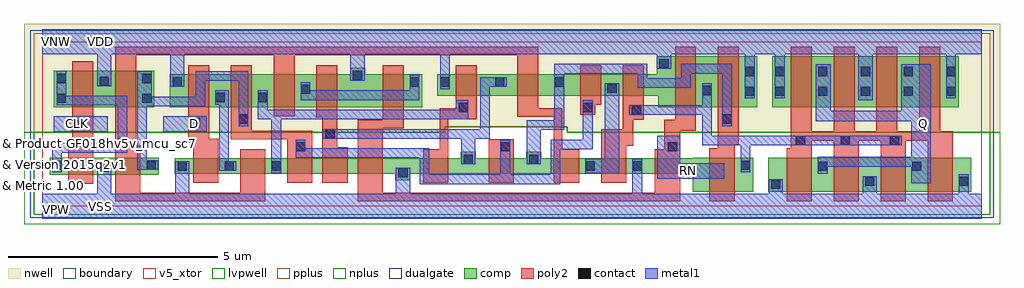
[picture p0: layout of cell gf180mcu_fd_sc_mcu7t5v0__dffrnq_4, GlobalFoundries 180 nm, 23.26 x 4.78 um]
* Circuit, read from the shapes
.subckt gf180mcu_fd_sc_mcu7t5v0__dffrnq_4 CLK D Q RN VDD VNW VSS
XM1 VSS CLK n1 VSUBS nfet_05v0 w=0.405u l=0.6u
XM2 n2 n1 VSS VSUBS nfet_05v0 w=0.405u l=0.6u
XM3 n3 D VSS VSUBS nfet_05v0 w=0.36u l=0.6u
XM4 n4 n1 n3 VSUBS nfet_05v0 w=0.36u l=0.6u
XM5 n5 n2 n4 VSUBS nfet_05v0 w=0.36u l=0.6u
XM6 n6 n7 n5 VSUBS nfet_05v0 w=0.36u l=0.6u
XM7 VSS RN n6 VSUBS nfet_05v0 w=0.36u l=0.6u
XM8 n7 n4 VSS VSUBS nfet_05v0 w=0.36u l=0.6u
XM9 n8 n2 n7 VSUBS nfet_05v0 w=0.36u l=0.6u
XM10 n9 n1 n8 VSUBS nfet_05v0 w=0.36u l=0.6u
XM11 VSS n10 n9 VSUBS nfet_05v0 w=0.36u l=0.6u
XM12 n11 RN VSS VSUBS nfet_05v0 w=0.36u l=0.6u
XM13 n10 n8 n11 VSUBS nfet_05v0 w=0.815u l=0.6u
XM14 Q n10 VSS VSUBS nfet_05v0 w=0.815u l=0.6u m=4
XM15 VDD CLK n1 VNW pfet_05v0 w=0.865u l=0.5u
XM16 n2 n1 VDD VNW pfet_05v0 w=0.865u l=0.5u
XM17 n3 D VDD VNW pfet_05v0 w=0.78u l=0.5u
XM18 n4 n2 n3 VNW pfet_05v0 w=0.78u l=0.5u
XM19 n12 n1 n4 VNW pfet_05v0 w=0.78u l=0.5u
XM20 VDD n7 n12 VNW pfet_05v0 w=0.78u l=0.5u
XM21 n12 RN VDD VNW pfet_05v0 w=0.78u l=0.5u
XM22 n7 n4 VDD VNW pfet_05v0 w=0.505u l=0.5u
XM23 n8 n1 n7 VNW pfet_05v0 w=0.505u l=0.5u
XM24 n9 n2 n8 VNW pfet_05v0 w=0.505u l=0.5u
XM25 VDD n10 n9 VNW pfet_05v0 w=0.505u l=0.5u
XM26 n10 RN VDD VNW pfet_05v0 w=1.215u l=0.5u
XM27 VDD n8 n10 VNW pfet_05v0 w=1.215u l=0.5u
XM28 Q n10 VDD VNW pfet_05v0 w=1.215u l=0.5u m=4
.ends

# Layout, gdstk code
import gdstk
lib = gdstk.Library(unit=1e-6, precision=5e-09)
def R(c, l, rs):  # rectangles x0, y0, x1, y1
    for r in rs: c.add(gdstk.rectangle(r[:2], r[2:], *l))
def A(c, l, x, y, w, h, nx, ny, dx, dy):  # array of equal rectangles
    R(c, l, [(x+i*dx, y+j*dy, x+i*dx+w, y+j*dy+h) for i in range(nx) for j in range(ny)])
def P(c, l, *ps):  # polygons
    for p in ps: c.add(gdstk.Polygon(p, *l))
boundary = (0, 0)
nwell = (21, 0)
comp = (22, 0)
poly2 = (30, 0)
pplus = (31, 0)
nplus = (32, 0)
contact = (33, 0)
metal1 = (34, 0)
dualgate = (55, 0)
v5_xtor = (112, 1)
lvpwell = (204, 0)

gf180mcu_fd_sc_mcu7t5v0_ = lib.new_cell('gf180mcu_fd_sc_mcu7t5v0__dffrnq_4')
R(gf180mcu_fd_sc_mcu7t5v0_, boundary, [(0,0,22.4,3.92)])
P(gf180mcu_fd_sc_mcu7t5v0_, nwell, [(-0.43,1.76),(-0.43,4.35),(22.83,4.35),(22.83,1.76),(12.515,1.76),(12.515,1.895),(9.6,1.895),(9.6,1.76)])
R(gf180mcu_fd_sc_mcu7t5v0_, comp, [(17.305,0.345,22.145,1.16), (0.18,0.755,2.78,1.16), (0.28,2.36,2.68,3.225), (17.405,2.36,21.845,3.575)])
P(gf180mcu_fd_sc_mcu7t5v0_, comp, [(3.04,2.36),(3.04,3.14),(7.34,3.14),(7.34,3.3),(7.7,3.3),(7.7,3.14),(9.06,3.14),(9.06,2.36)],
  [(15.505,0.345),(15.505,0.78),(8.78,0.78),(8.78,0.62),(8.42,0.62),(8.42,0.78),(3.16,0.78),(3.16,1.14),(9.98,1.14),(9.98,1.295),(10.34,1.295),(10.34,1.14),(11.54,1.14),(11.54,1.295),(11.9,1.295),(11.9,1.14),(15.505,1.14),(15.505,1.16),(16.945,1.16),(16.945,0.345)],
  [(14.685,2.36),(14.685,2.635),(9.42,2.635),(9.42,3.14),(14.645,3.14),(14.645,3.575),(17.045,3.575),(17.045,2.36)])
R(gf180mcu_fd_sc_mcu7t5v0_, poly2, [(10.64,0.56,11.24,1.6)])
P(gf180mcu_fd_sc_mcu7t5v0_, poly2, [(0.62,0.535),(0.62,1.44),(0.72,1.44),(0.72,3.45),(1.22,3.45),(1.22,0.535)],
  [(3.6,0.56),(3.6,1.51),(3.48,1.51),(3.48,3.36),(3.98,3.36),(3.98,1.61),(4.2,1.61),(4.2,0.56)],
  [(5.84,0.56),(5.84,1.6),(4.5,1.6),(4.5,3.36),(5,3.36),(5,1.8),(6.44,1.8),(6.44,0.56)],
  [(6.68,0.56),(6.68,2.115),(6.54,2.115),(6.54,3.36),(7.04,3.36),(7.04,1.4),(7.28,1.4),(7.28,0.56)],
  [(9.08,0.56),(9.08,1.36),(9.48,1.36),(9.48,2.335),(9.86,2.335),(9.86,3.36),(10.36,3.36),(10.36,2.07),(9.68,2.07),(9.68,0.56)],
  [(1.74,0.12),(1.74,3.8),(11.82,3.8),(11.82,2.335),(12.4,2.335),(12.4,1.36),(12.8,1.36),(12.8,0.56),(12.2,0.56),(12.2,2.135),(11.32,2.135),(11.32,3.6),(6.02,3.6),(6.02,2.14),(5.52,2.14),(5.52,3.6),(2.24,3.6),(2.24,1.44),(2.34,1.44),(2.34,0.32),(4.72,0.32),(4.72,1.36),(5.32,1.36),(5.32,0.12)],
  [(12.825,2.175),(12.825,3.36),(13.325,3.36),(13.325,2.415),(13.185,2.415),(13.185,2.175)],
  [(13.325,0.56),(13.325,1.84),(13.845,1.84),(13.845,3.36),(14.345,3.36),(14.345,2.06),(14.085,2.06),(14.085,1.44),(13.925,1.44),(13.925,0.56)],
  [(7.52,0.12),(7.52,2.06),(8.12,2.06),(8.12,3.36),(8.62,3.36),(8.62,1.86),(8.12,1.86),(8.12,0.32),(14.605,0.32),(14.605,1.36),(14.825,1.36),(14.825,2.06),(15.085,2.06),(15.085,3.8),(15.585,3.8),(15.585,1.805),(15.205,1.805),(15.205,0.12)],
  [(15.905,0.12),(15.905,1.38),(16.105,1.38),(16.105,3.8),(16.605,3.8),(16.605,1.46),(16.505,1.46),(16.505,0.12)],
  [(17.745,0.12),(17.745,1.38),(17.845,1.38),(17.845,3.8),(18.345,3.8),(18.345,1.785),(18.865,1.785),(18.865,3.8),(19.365,3.8),(19.365,1.785),(19.885,1.785),(19.885,3.8),(20.385,3.8),(20.385,1.79),(20.905,1.79),(20.905,3.8),(21.405,3.8),(21.405,1.785),(21.705,1.785),(21.705,0.12),(21.105,0.12),(21.105,1.555),(20.585,1.555),(20.585,0.12),(19.985,0.12),(19.985,1.555),(19.465,1.555),(19.465,0.12),(18.865,0.12),(18.865,1.555),(18.345,1.555),(18.345,0.12)])
P(gf180mcu_fd_sc_mcu7t5v0_, pplus, [(-0.2,1.76),(-0.2,4.12),(22.6,4.12),(22.6,1.76),(12.515,1.76),(12.515,1.895),(9.6,1.895),(9.6,1.76)])
P(gf180mcu_fd_sc_mcu7t5v0_, nplus, [(-0.2,-0.2),(-0.2,1.76),(9.6,1.76),(9.6,1.895),(12.515,1.895),(12.515,1.76),(22.6,1.76),(22.6,-0.2)])
A(gf180mcu_fd_sc_mcu7t5v0_, contact, 3.23, 0.85, 0.22, 0.22, 3, 1, 1.12, 0)
A(gf180mcu_fd_sc_mcu7t5v0_, contact, 17.475, 2.63, 0.22, 0.22, 5, 2, 1.02, 0.47)
R(gf180mcu_fd_sc_mcu7t5v0_, contact, [(17.375,0.415,17.595,0.635), (19.615,0.485,19.835,0.705), (21.855,0.485,22.075,0.705), (8.49,0.69,8.71,0.91), (1.37,0.825,1.59,1.045), (18.495,0.84,18.715,1.06), (20.735,0.84,20.955,1.06), (12.955,0.85,13.175,1.07), (14.075,0.85,14.295,1.07), (0.25,0.87,0.47,1.09), (2.49,0.87,2.71,1.09), (16.655,0.87,16.875,1.09), (10.05,1.005,10.27,1.225), (11.61,1.005,11.83,1.225), (6.05,1.31,6.27,1.53), (10.93,1.31,11.15,1.53), (14.915,1.31,15.135,1.53), (1.81,1.405,2.03,1.625), (17.965,1.455,18.185,1.675), (19.03,1.455,19.25,1.675), (20.205,1.455,20.425,1.675), (6.75,1.615,6.97,1.835), (0.79,1.835,1.01,2.055), (3.55,1.885,3.77,2.105), (4.69,1.97,4.91,2.19), (16.215,1.97,16.435,2.19), (14.055,2.18,14.275,2.4), (9.93,2.245,10.15,2.465), (12.895,2.245,13.115,2.465), (0.35,2.465,0.57,2.685), (2.39,2.465,2.61,2.685), (4.13,2.48,4.35,2.7), (5.15,2.48,5.37,2.7), (16.755,2.63,16.975,2.85), (15.735,2.65,15.955,2.87), (6.17,2.675,6.39,2.895), (13.475,2.705,13.695,2.925), (3.11,2.85,3.33,3.07), (8.77,2.85,8.99,3.07), (9.49,2.85,9.71,3.07), (10.8,2.85,11.02,3.07), (12.215,2.85,12.435,3.07), (1.37,2.87,1.59,3.09), (0.35,2.935,0.57,3.155), (2.39,2.935,2.61,3.155), (7.41,3.01,7.63,3.23), (16.755,3.1,16.975,3.32), (14.715,3.285,14.935,3.505)])
R(gf180mcu_fd_sc_mcu7t5v0_, metal1, [(0.28,1.77,1.57,2.15), (2.89,1.77,3.92,2.15)])
P(gf180mcu_fd_sc_mcu7t5v0_, metal1, [(0.245,0.81),(0.245,1.51),(1.805,1.51),(1.805,2.405),(0.345,2.405),(0.345,3.225),(0.575,3.225),(0.575,2.635),(2.035,2.635),(2.035,1.28),(0.475,1.28),(0.475,0.81)],
  [(4.225,0.845),(4.225,2.42),(4.125,2.42),(4.125,2.76),(4.455,2.76),(4.455,1.075),(4.63,1.075),(4.63,0.845)],
  [(2.265,0.865),(2.265,3.215),(2.615,3.215),(2.615,2.615),(3.665,2.615),(3.665,3.22),(4.915,3.22),(4.915,1.91),(4.685,1.91),(4.685,2.99),(3.895,2.99),(3.895,2.385),(2.495,2.385),(2.495,1.095),(2.77,1.095),(2.77,0.865)],
  [(6.165,2.53),(6.165,2.955),(6.395,2.955),(6.395,2.76),(8.765,2.76),(8.765,3.13),(8.995,3.13),(8.995,2.53)],
  [(5.465,0.79),(5.465,2.07),(5.145,2.07),(5.145,2.76),(5.375,2.76),(5.375,2.3),(9.855,2.3),(9.855,2.525),(10.155,2.525),(10.155,2.07),(5.695,2.07),(5.695,0.79)],
  [(9.99,1),(9.99,1.61),(6.69,1.61),(6.69,1.84),(10.44,1.84),(10.44,3.075),(11.08,3.075),(11.08,2.845),(10.67,2.845),(10.67,1.61),(10.33,1.61),(10.33,1)],
  [(9,0.53),(9,1.15),(6.045,1.15),(6.045,1.59),(6.275,1.59),(6.275,1.38),(9.23,1.38),(9.23,0.76),(10.925,0.76),(10.925,1.59),(11.155,1.59),(11.155,0.76),(12.12,0.76),(12.12,1.59),(12.89,1.59),(12.89,2.525),(13.12,2.525),(13.12,1.36),(12.35,1.36),(12.35,0.53)],
  [(12.95,0.79),(12.95,1.13),(13.415,1.13),(13.415,2.93),(13.755,2.93),(13.755,0.79)],
  [(14.66,0.66),(14.66,1.685),(15.21,1.685),(15.21,1.025),(16.255,1.025),(16.255,0.66)],
  [(11.55,1),(11.55,2.05),(12.21,2.05),(12.21,3.39),(14.425,3.39),(14.425,3.05),(15.235,3.05),(15.235,3.39),(16.44,3.39),(16.44,1.91),(16.21,1.91),(16.21,3.16),(15.465,3.16),(15.465,2.82),(14.195,2.82),(14.195,3.16),(12.44,3.16),(12.44,1.82),(11.89,1.82),(11.89,1)],
  [(16.65,0.81),(16.65,1.45),(15.73,1.45),(15.73,2.175),(13.995,2.175),(13.995,2.405),(15.73,2.405),(15.73,2.93),(15.96,2.93),(15.96,1.68),(20.485,1.68),(20.485,1.45),(16.88,1.45),(16.88,0.81)],
  [(20.715,0.55),(20.715,0.94),(18.72,0.94),(18.72,0.78),(18.49,0.78),(18.49,1.175),(20.715,1.175),(20.715,2.03),(18.435,2.03),(18.435,3.38),(18.8,3.38),(18.8,2.28),(20.475,2.28),(20.475,3.38),(21.18,3.38),(21.18,0.55)],
  [(0,-0.3),(0,0.3),(1.31,0.3),(1.31,1.05),(1.655,1.05),(1.655,0.3),(3.17,0.3),(3.17,1.075),(3.51,1.075),(3.51,0.3),(8.43,0.3),(8.43,0.915),(8.77,0.915),(8.77,0.3),(14.07,0.3),(14.07,1.13),(14.3,1.13),(14.3,0.3),(17.315,0.3),(17.315,0.64),(17.655,0.64),(17.655,0.3),(19.555,0.3),(19.555,0.71),(19.895,0.71),(19.895,0.3),(21.85,0.3),(21.85,0.765),(22.08,0.765),(22.08,0.3),(22.4,0.3),(22.4,-0.3)],
  [(19.455,2.53),(19.455,3.62),(17.7,3.62),(17.7,2.57),(17.465,2.57),(17.465,3.62),(16.985,3.62),(16.985,2.57),(16.75,2.57),(16.75,3.62),(14.995,3.62),(14.995,3.28),(14.655,3.28),(14.655,3.62),(9.715,3.62),(9.715,2.79),(9.485,2.79),(9.485,3.62),(7.69,3.62),(7.69,2.99),(7.35,2.99),(7.35,3.62),(3.39,3.62),(3.39,2.845),(3.05,2.845),(3.05,3.62),(1.65,3.62),(1.65,2.865),(1.31,2.865),(1.31,3.62),(0,3.62),(0,4.22),(22.4,4.22),(22.4,3.62),(21.78,3.62),(21.78,2.57),(21.55,2.57),(21.55,3.62),(19.795,3.62),(19.795,2.53)])
R(gf180mcu_fd_sc_mcu7t5v0_, dualgate, [(-0.28,-0.28,22.68,4.2)])
R(gf180mcu_fd_sc_mcu7t5v0_, v5_xtor, [(0,0,22.4,3.92)])
P(gf180mcu_fd_sc_mcu7t5v0_, lvpwell, [(-0.43,-0.43),(-0.43,1.76),(9.6,1.76),(9.6,1.895),(12.515,1.895),(12.515,1.76),(22.83,1.76),(22.83,-0.43)])
gf180mcu_fd_sc_mcu7t5v0_.add(gdstk.Label('D', (3.64,1.96), layer=34, texttype=10))
gf180mcu_fd_sc_mcu7t5v0_.add(gdstk.Label('Q', (21,1.96), layer=34, texttype=10))
gf180mcu_fd_sc_mcu7t5v0_.add(gdstk.Label('RN', (15.4,0.84), layer=34, texttype=10))
gf180mcu_fd_sc_mcu7t5v0_.add(gdstk.Label('VDD', (1.4,3.92), layer=34, texttype=10))
gf180mcu_fd_sc_mcu7t5v0_.add(gdstk.Label('VSS', (1.4,0), layer=34, texttype=10))
gf180mcu_fd_sc_mcu7t5v0_.add(gdstk.Label('CLK', (0.84,1.96), layer=34, texttype=10))
gf180mcu_fd_sc_mcu7t5v0_.add(gdstk.Label('& Vendor GLOBALFOUNDRIES', (0,2), layer=63, texttype=63))
gf180mcu_fd_sc_mcu7t5v0_.add(gdstk.Label('& Product GF018hv5v_mcu_sc7', (0,1.5), layer=63, texttype=63))
gf180mcu_fd_sc_mcu7t5v0_.add(gdstk.Label('& Version 2015q2v1', (0,1), layer=63, texttype=63))
gf180mcu_fd_sc_mcu7t5v0_.add(gdstk.Label('& Metric 1.00', (0,0.5), layer=63, texttype=63))
gf180mcu_fd_sc_mcu7t5v0_.add(gdstk.Label('VNW', (0.345,3.92), layer=21, texttype=10))
gf180mcu_fd_sc_mcu7t5v0_.add(gdstk.Label('VPW', (0.34,-0.085), layer=204, texttype=10))

lib.write_gds('gf180mcu_fd_sc_mcu7t5v0__dffrnq_4.gds')
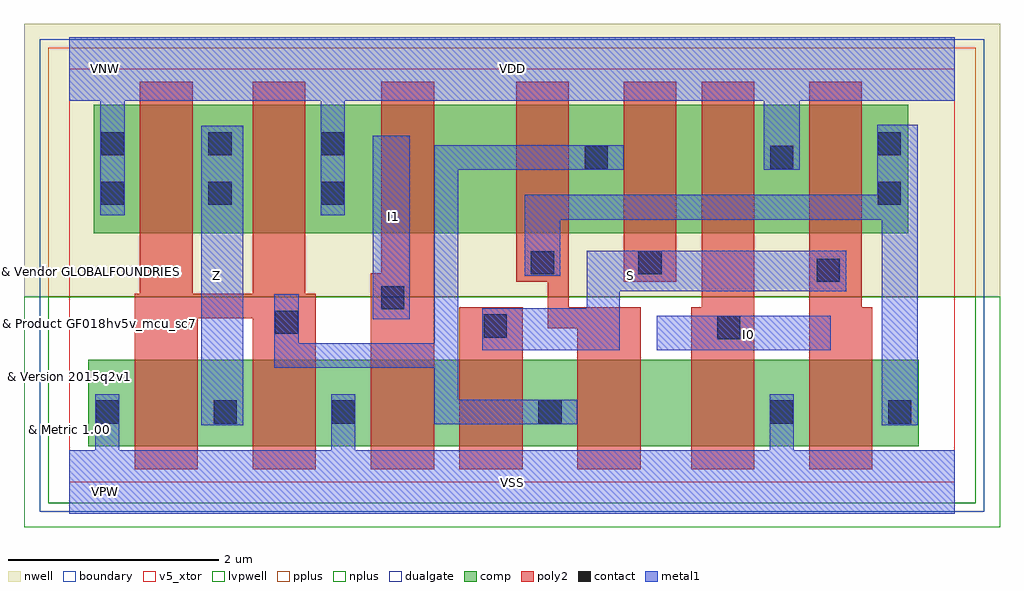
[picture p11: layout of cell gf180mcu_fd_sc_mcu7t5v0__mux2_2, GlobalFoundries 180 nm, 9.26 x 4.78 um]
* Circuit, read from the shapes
.subckt gf180mcu_fd_sc_mcu7t5v0__mux2_2 I0 I1 S VDD VNW VSS Z
XM1 Z n1 VSS VSUBS nfet_05v0 w=0.82u l=0.6u m=2
XM2 n2 I1 VSS VSUBS nfet_05v0 w=0.82u l=0.6u
XM3 n1 S n2 VSUBS nfet_05v0 w=0.82u l=0.6u
XM4 n3 n4 n1 VSUBS nfet_05v0 w=0.82u l=0.6u
XM5 VSS I0 n3 VSUBS nfet_05v0 w=0.82u l=0.6u
XM6 n4 S VSS VSUBS nfet_05v0 w=0.82u l=0.6u
XM7 Z n1 VDD VNW pfet_05v0 w=1.22u l=0.5u m=2
XM8 n5 I1 VDD VNW pfet_05v0 w=1.22u l=0.5u
XM9 n1 n4 n5 VNW pfet_05v0 w=1.22u l=0.5u
XM10 n6 S n1 VNW pfet_05v0 w=1.22u l=0.5u
XM11 VDD I0 n6 VNW pfet_05v0 w=1.22u l=0.5u
XM12 n4 S VDD VNW pfet_05v0 w=1.22u l=0.5u
.ends

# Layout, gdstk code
import gdstk
lib = gdstk.Library(unit=1e-6, precision=5e-09)
def R(c, l, rs):  # rectangles x0, y0, x1, y1
    for r in rs: c.add(gdstk.rectangle(r[:2], r[2:], *l))
def A(c, l, x, y, w, h, nx, ny, dx, dy):  # array of equal rectangles
    R(c, l, [(x+i*dx, y+j*dy, x+i*dx+w, y+j*dy+h) for i in range(nx) for j in range(ny)])
def P(c, l, *ps):  # polygons
    for p in ps: c.add(gdstk.Polygon(p, *l))
boundary = (0, 0)
nwell = (21, 0)
comp = (22, 0)
poly2 = (30, 0)
pplus = (31, 0)
nplus = (32, 0)
contact = (33, 0)
metal1 = (34, 0)
dualgate = (55, 0)
v5_xtor = (112, 1)
lvpwell = (204, 0)

gf180mcu_fd_sc_mcu7t5v0_ = lib.new_cell('gf180mcu_fd_sc_mcu7t5v0__mux2_2')
R(gf180mcu_fd_sc_mcu7t5v0_, boundary, [(0,0,8.4,3.92)])
R(gf180mcu_fd_sc_mcu7t5v0_, nwell, [(-0.43,1.76,8.83,4.35)])
R(gf180mcu_fd_sc_mcu7t5v0_, comp, [(0.18,0.34,8.06,1.16), (0.23,2.36,7.96,3.58)])
R(gf180mcu_fd_sc_mcu7t5v0_, poly2, [(3.7,0.12,4.3,1.66), (5.26,1.9,5.76,3.8)])
P(gf180mcu_fd_sc_mcu7t5v0_, poly2, [(0.62,0.12),(0.62,1.785),(0.67,1.785),(0.67,3.8),(1.17,3.8),(1.17,1.785),(1.74,1.785),(1.74,3.8),(2.24,3.8),(2.24,1.785),(2.34,1.785),(2.34,0.12),(1.74,0.12),(1.74,1.555),(1.22,1.555),(1.22,0.12)],
  [(2.86,0.12),(2.86,1.98),(2.96,1.98),(2.96,3.8),(3.46,3.8),(3.46,0.12)],
  [(4.82,0.12),(4.82,1.46),(4.54,1.46),(4.54,1.9),(4.24,1.9),(4.24,3.8),(4.74,3.8),(4.74,1.66),(5.42,1.66),(5.42,0.12)],
  [(5.9,0.12),(5.9,1.66),(6,1.66),(6,3.8),(6.5,3.8),(6.5,0.12)],
  [(7.02,0.12),(7.02,3.8),(7.52,3.8),(7.52,1.66),(7.62,1.66),(7.62,0.12)])
R(gf180mcu_fd_sc_mcu7t5v0_, pplus, [(-0.2,1.76,8.6,4.12)])
R(gf180mcu_fd_sc_mcu7t5v0_, nplus, [(-0.2,-0.2,8.6,1.76)])
A(gf180mcu_fd_sc_mcu7t5v0_, contact, 0.25, 0.555, 0.22, 0.22, 3, 1, 1.12, 0)
R(gf180mcu_fd_sc_mcu7t5v0_, contact, [(4.45,0.555,4.67,0.775), (6.65,0.555,6.87,0.775), (7.77,0.555,7.99,0.775), (6.145,1.355,6.365,1.575), (3.93,1.37,4.15,1.59), (1.95,1.405,2.17,1.625), (2.96,1.64,3.18,1.86), (7.09,1.9,7.31,2.12), (4.38,1.97,4.6,2.19), (5.4,1.97,5.62,2.19), (0.3,2.63,0.52,2.85), (1.32,2.63,1.54,2.85), (2.39,2.63,2.61,2.85), (7.67,2.63,7.89,2.85), (4.89,2.97,5.11,3.19), (6.65,2.97,6.87,3.19), (0.3,3.1,0.52,3.32), (1.32,3.1,1.54,3.32), (2.39,3.1,2.61,3.32), (7.67,3.1,7.89,3.32)])
R(gf180mcu_fd_sc_mcu7t5v0_, metal1, [(1.25,0.54,1.65,3.38), (5.575,1.25,7.225,1.58), (2.88,1.545,3.23,3.285)])
P(gf180mcu_fd_sc_mcu7t5v0_, metal1, [(3.46,0.55),(3.46,1.085),(1.945,1.085),(1.945,1.78),(2.175,1.78),(2.175,1.315),(3.46,1.315),(3.46,3.195),(5.26,3.195),(5.26,2.965),(3.69,2.965),(3.69,0.78),(4.82,0.78),(4.82,0.55)],
  [(3.92,1.25),(3.92,1.65),(4.91,1.65),(4.91,2.195),(7.37,2.195),(7.37,1.81),(5.22,1.81),(5.22,1.25)],
  [(7.71,0.54),(7.71,2.49),(4.66,2.49),(4.66,1.96),(4.32,1.96),(4.32,2.725),(7.665,2.725),(7.665,3.39),(8.05,3.39),(8.05,0.54)],
  [(0,-0.3),(0,0.3),(0.245,0.3),(0.245,0.835),(0.475,0.835),(0.475,0.3),(2.485,0.3),(2.485,0.835),(2.715,0.835),(2.715,0.3),(6.645,0.3),(6.645,0.835),(6.875,0.835),(6.875,0.3),(8.4,0.3),(8.4,-0.3)],
  [(0.295,2.53),(0.295,3.62),(0,3.62),(0,4.22),(8.4,4.22),(8.4,3.62),(6.93,3.62),(6.93,2.965),(6.59,2.965),(6.59,3.62),(2.615,3.62),(2.615,2.53),(2.385,2.53),(2.385,3.62),(0.525,3.62),(0.525,2.53)])
R(gf180mcu_fd_sc_mcu7t5v0_, dualgate, [(-0.28,-0.28,8.68,4.2)])
R(gf180mcu_fd_sc_mcu7t5v0_, v5_xtor, [(0,0,8.4,3.92)])
R(gf180mcu_fd_sc_mcu7t5v0_, lvpwell, [(-0.43,-0.43,8.83,1.76)])
gf180mcu_fd_sc_mcu7t5v0_.add(gdstk.Label('S', (5.32,1.96), layer=34, texttype=10))
gf180mcu_fd_sc_mcu7t5v0_.add(gdstk.Label('VDD', (4.2,3.92), layer=34, texttype=10))
gf180mcu_fd_sc_mcu7t5v0_.add(gdstk.Label('VSS', (4.2,0), layer=34, texttype=10))
gf180mcu_fd_sc_mcu7t5v0_.add(gdstk.Label('Z', (1.4,1.96), layer=34, texttype=10))
gf180mcu_fd_sc_mcu7t5v0_.add(gdstk.Label('I0', (6.44,1.4), layer=34, texttype=10))
gf180mcu_fd_sc_mcu7t5v0_.add(gdstk.Label('I1', (3.08,2.52), layer=34, texttype=10))
gf180mcu_fd_sc_mcu7t5v0_.add(gdstk.Label('& Vendor GLOBALFOUNDRIES', (0,2), layer=63, texttype=63))
gf180mcu_fd_sc_mcu7t5v0_.add(gdstk.Label('& Product GF018hv5v_mcu_sc7', (0,1.5), layer=63, texttype=63))
gf180mcu_fd_sc_mcu7t5v0_.add(gdstk.Label('& Version 2015q2v1', (0,1), layer=63, texttype=63))
gf180mcu_fd_sc_mcu7t5v0_.add(gdstk.Label('& Metric 1.00', (0,0.5), layer=63, texttype=63))
gf180mcu_fd_sc_mcu7t5v0_.add(gdstk.Label('VNW', (0.345,3.92), layer=21, texttype=10))
gf180mcu_fd_sc_mcu7t5v0_.add(gdstk.Label('VPW', (0.34,-0.085), layer=204, texttype=10))

lib.write_gds('gf180mcu_fd_sc_mcu7t5v0__mux2_2.gds')
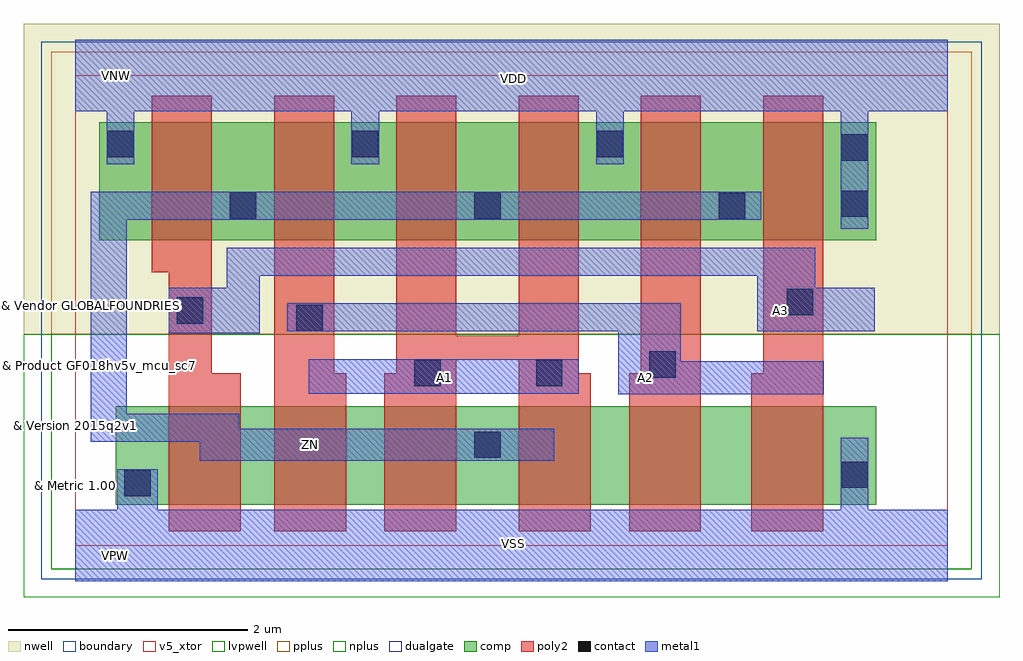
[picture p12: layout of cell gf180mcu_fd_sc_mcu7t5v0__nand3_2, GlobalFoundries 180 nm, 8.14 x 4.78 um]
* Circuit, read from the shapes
.subckt gf180mcu_fd_sc_mcu7t5v0__nand3_2 A1 A2 A3 VDD VNW VSS ZN
XM1 n1 A3 VSS VSUBS nfet_05v0 w=0.82u l=0.6u
XM2 n2 A2 n1 VSUBS nfet_05v0 w=0.82u l=0.6u
XM3 ZN A1 n2 VSUBS nfet_05v0 w=0.82u l=0.6u
XM4 n3 A1 ZN VSUBS nfet_05v0 w=0.82u l=0.6u
XM5 n4 A2 n3 VSUBS nfet_05v0 w=0.82u l=0.6u
XM6 VSS A3 n4 VSUBS nfet_05v0 w=0.82u l=0.6u
XM7 ZN A3 VDD VNW pfet_05v0 w=0.985u l=0.5u m=2
XM8 VDD A2 ZN VNW pfet_05v0 w=0.985u l=0.5u m=2
XM9 ZN A1 VDD VNW pfet_05v0 w=0.985u l=0.5u m=2
.ends

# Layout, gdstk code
import gdstk
lib = gdstk.Library(unit=1e-6, precision=5e-09)
def R(c, l, rs):  # rectangles x0, y0, x1, y1
    for r in rs: c.add(gdstk.rectangle(r[:2], r[2:], *l))
def A(c, l, x, y, w, h, nx, ny, dx, dy):  # array of equal rectangles
    R(c, l, [(x+i*dx, y+j*dy, x+i*dx+w, y+j*dy+h) for i in range(nx) for j in range(ny)])
def P(c, l, *ps):  # polygons
    for p in ps: c.add(gdstk.Polygon(p, *l))
boundary = (0, 0)
nwell = (21, 0)
comp = (22, 0)
poly2 = (30, 0)
pplus = (31, 0)
nplus = (32, 0)
contact = (33, 0)
metal1 = (34, 0)
dualgate = (55, 0)
v5_xtor = (112, 1)
lvpwell = (204, 0)

gf180mcu_fd_sc_mcu7t5v0_ = lib.new_cell('gf180mcu_fd_sc_mcu7t5v0__nand3_2')
R(gf180mcu_fd_sc_mcu7t5v0_, boundary, [(0,0,7.28,3.92)])
R(gf180mcu_fd_sc_mcu7t5v0_, nwell, [(-0.43,1.76,7.71,4.35)])
R(gf180mcu_fd_sc_mcu7t5v0_, comp, [(0.34,0.34,6.68,1.16), (0.2,2.545,6.68,3.53)])
P(gf180mcu_fd_sc_mcu7t5v0_, poly2, [(0.78,0.12),(0.78,2.28),(0.64,2.28),(0.64,3.75),(1.14,3.75),(1.14,1.435),(1.38,1.435),(1.38,0.12)],
  [(1.66,0.12),(1.66,3.75),(2.16,3.75),(2.16,1.435),(2.26,1.435),(2.26,0.12)],
  [(2.58,0.12),(2.58,1.435),(2.68,1.435),(2.68,3.75),(3.18,3.75),(3.18,1.75),(3.7,1.75),(3.7,3.75),(4.2,3.75),(4.2,1.435),(4.3,1.435),(4.3,0.12),(3.7,0.12),(3.7,1.55),(3.18,1.55),(3.18,0.12)],
  [(4.62,0.12),(4.62,1.435),(4.72,1.435),(4.72,3.75),(5.22,3.75),(5.22,0.12)],
  [(5.64,0.12),(5.64,1.435),(5.74,1.435),(5.74,3.75),(6.24,3.75),(6.24,0.12)])
R(gf180mcu_fd_sc_mcu7t5v0_, pplus, [(-0.2,1.76,7.48,4.12)])
R(gf180mcu_fd_sc_mcu7t5v0_, nplus, [(-0.2,-0.2,7.48,1.76)])
A(gf180mcu_fd_sc_mcu7t5v0_, contact, 0.27, 3.24, 0.22, 0.22, 3, 1, 2.04, 0)
R(gf180mcu_fd_sc_mcu7t5v0_, contact, [(0.41,0.41,0.63,0.63), (6.39,0.48,6.61,0.7), (3.33,0.73,3.55,0.95), (2.83,1.33,3.05,1.55), (3.845,1.33,4.065,1.55), (4.79,1.4,5.01,1.62), (1.845,1.79,2.065,2.01), (0.85,1.85,1.07,2.07), (5.935,1.92,6.155,2.14), (5.37,2.72,5.59,2.94), (1.29,2.725,1.51,2.945), (3.33,2.725,3.55,2.945), (6.39,2.74,6.61,2.96), (6.39,3.21,6.61,3.43)])
R(gf180mcu_fd_sc_mcu7t5v0_, metal1, [(1.95,1.265,4.2,1.555)])
P(gf180mcu_fd_sc_mcu7t5v0_, metal1, [(1.04,0.705),(1.04,0.865),(0.13,0.865),(0.13,2.95),(5.725,2.95),(5.725,2.715),(0.43,2.715),(0.43,1.1),(1.37,1.1),(1.37,0.975),(3.995,0.975),(3.995,0.705)],
  [(4.53,1.26),(4.53,1.785),(1.77,1.785),(1.77,2.02),(5.05,2.02),(5.05,1.535),(6.245,1.535),(6.245,1.26)],
  [(0.78,1.77),(0.78,2.15),(1.265,2.15),(1.265,2.485),(6.175,2.485),(6.175,2.15),(6.67,2.15),(6.67,1.785),(5.69,1.785),(5.69,2.25),(1.54,2.25),(1.54,1.77)],
  [(0,-0.3),(0,0.3),(0.35,0.3),(0.35,0.635),(0.69,0.635),(0.69,0.3),(6.385,0.3),(6.385,0.9),(6.615,0.9),(6.615,0.3),(7.28,0.3),(7.28,-0.3)],
  [(6.385,2.64),(6.385,3.62),(4.575,3.62),(4.575,3.18),(4.345,3.18),(4.345,3.62),(2.535,3.62),(2.535,3.18),(2.305,3.18),(2.305,3.62),(0.495,3.62),(0.495,3.18),(0.265,3.18),(0.265,3.62),(0,3.62),(0,4.22),(7.28,4.22),(7.28,3.62),(6.615,3.62),(6.615,2.64)])
R(gf180mcu_fd_sc_mcu7t5v0_, dualgate, [(-0.28,-0.28,7.56,4.2)])
R(gf180mcu_fd_sc_mcu7t5v0_, v5_xtor, [(0,0,7.28,3.92)])
R(gf180mcu_fd_sc_mcu7t5v0_, lvpwell, [(-0.43,-0.43,7.71,1.76)])
gf180mcu_fd_sc_mcu7t5v0_.add(gdstk.Label('A3', (5.88,1.96), layer=34, texttype=10))
gf180mcu_fd_sc_mcu7t5v0_.add(gdstk.Label('VDD', (3.66,3.895), layer=34, texttype=10))
gf180mcu_fd_sc_mcu7t5v0_.add(gdstk.Label('VSS', (3.66,0.02), layer=34, texttype=10))
gf180mcu_fd_sc_mcu7t5v0_.add(gdstk.Label('ZN', (1.96,0.84), layer=34, texttype=10))
gf180mcu_fd_sc_mcu7t5v0_.add(gdstk.Label('A1', (3.08,1.4), layer=34, texttype=10))
gf180mcu_fd_sc_mcu7t5v0_.add(gdstk.Label('A2', (4.76,1.4), layer=34, texttype=10))
gf180mcu_fd_sc_mcu7t5v0_.add(gdstk.Label('& Vendor GLOBALFOUNDRIES', (0,2), layer=63, texttype=63))
gf180mcu_fd_sc_mcu7t5v0_.add(gdstk.Label('& Product GF018hv5v_mcu_sc7', (0,1.5), layer=63, texttype=63))
gf180mcu_fd_sc_mcu7t5v0_.add(gdstk.Label('& Version 2015q2v1', (0,1), layer=63, texttype=63))
gf180mcu_fd_sc_mcu7t5v0_.add(gdstk.Label('& Metric 1.00', (0,0.5), layer=63, texttype=63))
gf180mcu_fd_sc_mcu7t5v0_.add(gdstk.Label('VNW', (0.345,3.92), layer=21, texttype=10))
gf180mcu_fd_sc_mcu7t5v0_.add(gdstk.Label('VPW', (0.34,-0.085), layer=204, texttype=10))

lib.write_gds('gf180mcu_fd_sc_mcu7t5v0__nand3_2.gds')
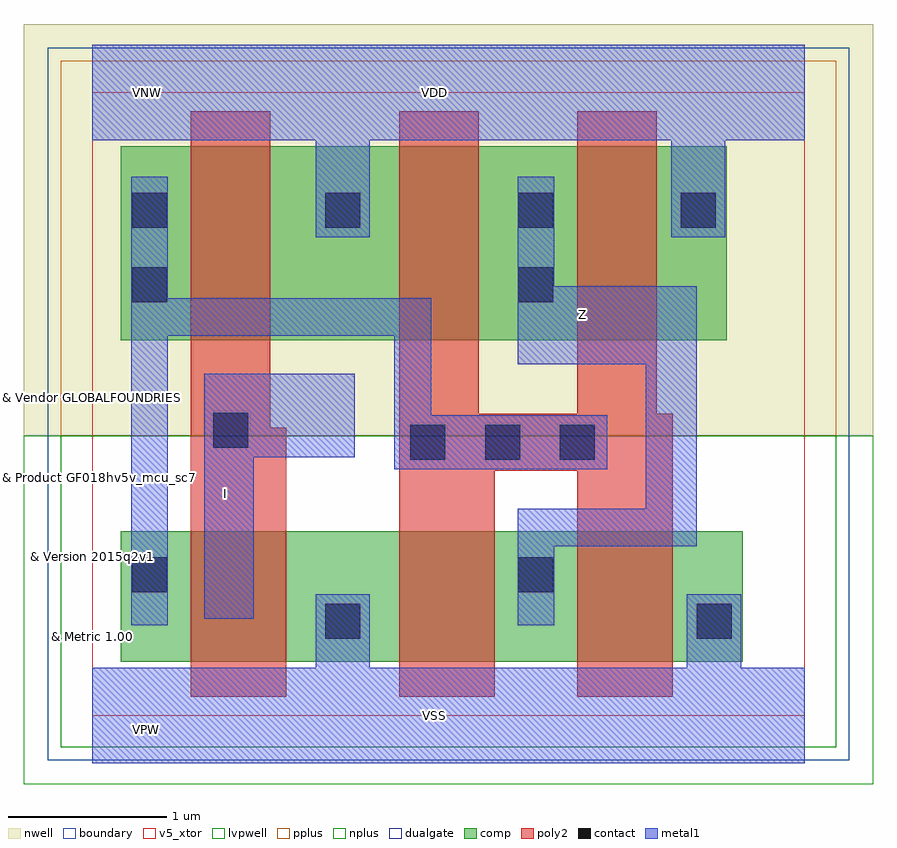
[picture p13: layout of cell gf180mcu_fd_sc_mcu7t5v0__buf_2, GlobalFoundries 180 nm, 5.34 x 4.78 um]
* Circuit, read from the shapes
.subckt gf180mcu_fd_sc_mcu7t5v0__buf_2 I VDD VNW VSS Z
XM1 VSS I n1 VSUBS nfet_05v0 w=0.82u l=0.6u
XM2 Z n1 VSS VSUBS nfet_05v0 w=0.82u l=0.6u m=2
XM3 VDD I n1 VNW pfet_05v0 w=1.22u l=0.5u
XM4 Z n1 VDD VNW pfet_05v0 w=1.22u l=0.5u m=2
.ends

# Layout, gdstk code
import gdstk
lib = gdstk.Library(unit=1e-6, precision=5e-09)
def R(c, l, rs):  # rectangles x0, y0, x1, y1
    for r in rs: c.add(gdstk.rectangle(r[:2], r[2:], *l))
def A(c, l, x, y, w, h, nx, ny, dx, dy):  # array of equal rectangles
    R(c, l, [(x+i*dx, y+j*dy, x+i*dx+w, y+j*dy+h) for i in range(nx) for j in range(ny)])
def P(c, l, *ps):  # polygons
    for p in ps: c.add(gdstk.Polygon(p, *l))
boundary = (0, 0)
nwell = (21, 0)
comp = (22, 0)
poly2 = (30, 0)
pplus = (31, 0)
nplus = (32, 0)
contact = (33, 0)
metal1 = (34, 0)
dualgate = (55, 0)
v5_xtor = (112, 1)
lvpwell = (204, 0)

gf180mcu_fd_sc_mcu7t5v0_ = lib.new_cell('gf180mcu_fd_sc_mcu7t5v0__buf_2')
R(gf180mcu_fd_sc_mcu7t5v0_, boundary, [(0,0,4.48,3.92)])
R(gf180mcu_fd_sc_mcu7t5v0_, nwell, [(-0.43,1.76,4.91,4.35)])
R(gf180mcu_fd_sc_mcu7t5v0_, comp, [(0.18,0.34,4.09,1.16), (0.18,2.36,3.99,3.58)])
P(gf180mcu_fd_sc_mcu7t5v0_, poly2, [(0.62,0.12),(0.62,3.8),(1.12,3.8),(1.12,1.81),(1.22,1.81),(1.22,0.12)],
  [(1.93,0.12),(1.93,3.8),(2.43,3.8),(2.43,1.9),(3.05,1.9),(3.05,3.8),(3.55,3.8),(3.55,1.9),(3.65,1.9),(3.65,0.12),(3.05,0.12),(3.05,1.54),(2.53,1.54),(2.53,0.12)])
R(gf180mcu_fd_sc_mcu7t5v0_, pplus, [(-0.2,1.76,4.68,4.12)])
R(gf180mcu_fd_sc_mcu7t5v0_, nplus, [(-0.2,-0.2,4.68,1.76)])
A(gf180mcu_fd_sc_mcu7t5v0_, contact, 2, 1.61, 0.22, 0.22, 3, 1, 0.47, 0)
A(gf180mcu_fd_sc_mcu7t5v0_, contact, 0.25, 3.07, 0.22, 0.22, 3, 1, 1.215, 0)
R(gf180mcu_fd_sc_mcu7t5v0_, contact, [(1.465,0.485,1.685,0.705), (3.8,0.485,4.02,0.705), (0.25,0.775,0.47,0.995), (2.68,0.775,2.9,0.995), (0.76,1.685,0.98,1.905), (0.25,2.6,0.47,2.82), (2.68,2.6,2.9,2.82), (3.7,3.07,3.92,3.29)])
P(gf180mcu_fd_sc_mcu7t5v0_, metal1, [(0.705,0.61),(0.705,2.15),(1.65,2.15),(1.65,1.625),(1.015,1.625),(1.015,0.61)],
  [(0.245,0.57),(0.245,3.39),(0.475,3.39),(0.475,2.625),(2.13,2.625),(2.13,1.89),(3.24,1.89),(3.24,1.55),(1.9,1.55),(1.9,2.39),(0.475,2.39),(0.475,0.57)],
  [(2.675,0.57),(2.675,1.3),(3.48,1.3),(3.48,2.21),(2.675,2.21),(2.675,3.39),(2.905,3.39),(2.905,2.7),(3.8,2.7),(3.8,1.065),(2.905,1.065),(2.905,0.57)],
  [(0,-0.3),(0,0.3),(1.405,0.3),(1.405,0.765),(1.745,0.765),(1.745,0.3),(3.74,0.3),(3.74,0.765),(4.08,0.765),(4.08,0.3),(4.48,0.3),(4.48,-0.3)],
  [(1.405,3.01),(1.405,3.62),(0,3.62),(0,4.22),(4.48,4.22),(4.48,3.62),(3.98,3.62),(3.98,3.01),(3.64,3.01),(3.64,3.62),(1.745,3.62),(1.745,3.01)])
R(gf180mcu_fd_sc_mcu7t5v0_, dualgate, [(-0.28,-0.28,4.76,4.2)])
R(gf180mcu_fd_sc_mcu7t5v0_, v5_xtor, [(0,0,4.48,3.92)])
R(gf180mcu_fd_sc_mcu7t5v0_, lvpwell, [(-0.43,-0.43,4.91,1.76)])
gf180mcu_fd_sc_mcu7t5v0_.add(gdstk.Label('VSS', (2.15,0), layer=34, texttype=10))
gf180mcu_fd_sc_mcu7t5v0_.add(gdstk.Label('Z', (3.08,2.52), layer=34, texttype=10))
gf180mcu_fd_sc_mcu7t5v0_.add(gdstk.Label('I', (0.84,1.4), layer=34, texttype=10))
gf180mcu_fd_sc_mcu7t5v0_.add(gdstk.Label('VDD', (2.15,3.92), layer=34, texttype=10))
gf180mcu_fd_sc_mcu7t5v0_.add(gdstk.Label('& Vendor GLOBALFOUNDRIES', (0,2), layer=63, texttype=63))
gf180mcu_fd_sc_mcu7t5v0_.add(gdstk.Label('& Product GF018hv5v_mcu_sc7', (0,1.5), layer=63, texttype=63))
gf180mcu_fd_sc_mcu7t5v0_.add(gdstk.Label('& Version 2015q2v1', (0,1), layer=63, texttype=63))
gf180mcu_fd_sc_mcu7t5v0_.add(gdstk.Label('& Metric 1.00', (0,0.5), layer=63, texttype=63))
gf180mcu_fd_sc_mcu7t5v0_.add(gdstk.Label('VNW', (0.345,3.92), layer=21, texttype=10))
gf180mcu_fd_sc_mcu7t5v0_.add(gdstk.Label('VPW', (0.34,-0.085), layer=204, texttype=10))

lib.write_gds('gf180mcu_fd_sc_mcu7t5v0__buf_2.gds')
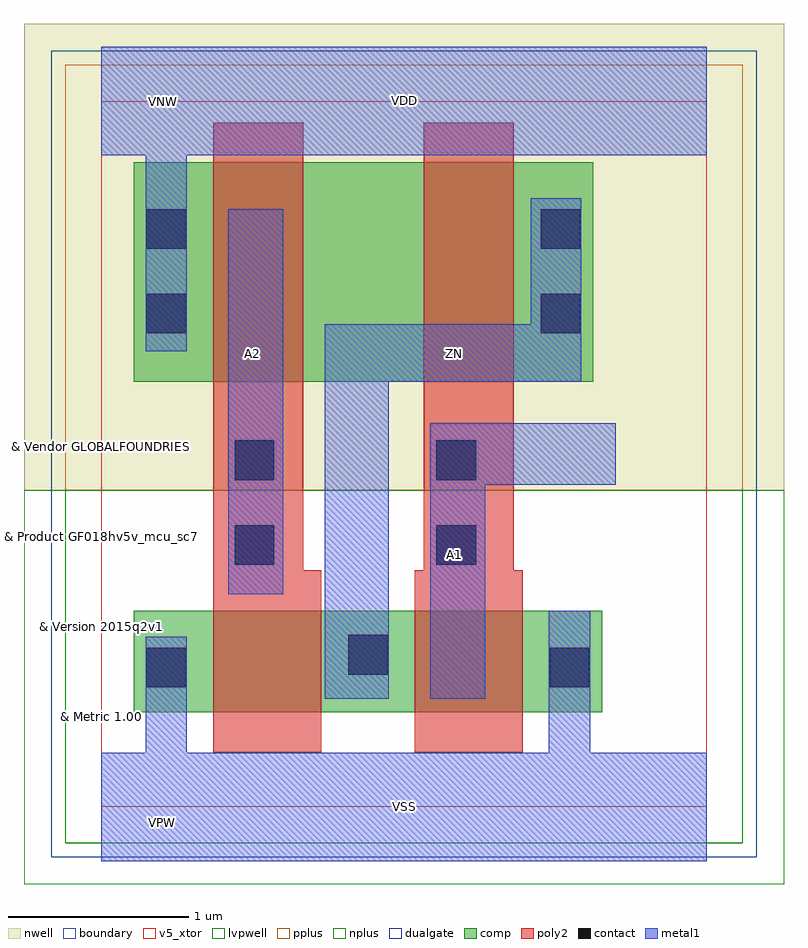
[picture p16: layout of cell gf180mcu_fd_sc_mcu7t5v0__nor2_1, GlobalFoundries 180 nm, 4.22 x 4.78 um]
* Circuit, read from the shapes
.subckt gf180mcu_fd_sc_mcu7t5v0__nor2_1 A1 A2 VDD VNW VSS ZN
XM1 ZN A2 VSS VSUBS nfet_05v0 w=0.565u l=0.6u
XM2 VSS A1 ZN VSUBS nfet_05v0 w=0.565u l=0.6u
XM3 n1 A2 VDD VNW pfet_05v0 w=1.22u l=0.5u
XM4 ZN A1 n1 VNW pfet_05v0 w=1.22u l=0.5u
.ends

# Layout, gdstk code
import gdstk
lib = gdstk.Library(unit=1e-6, precision=5e-09)
def R(c, l, rs):  # rectangles x0, y0, x1, y1
    for r in rs: c.add(gdstk.rectangle(r[:2], r[2:], *l))
def P(c, l, *ps):  # polygons
    for p in ps: c.add(gdstk.Polygon(p, *l))
boundary = (0, 0)
nwell = (21, 0)
comp = (22, 0)
poly2 = (30, 0)
pplus = (31, 0)
nplus = (32, 0)
contact = (33, 0)
metal1 = (34, 0)
dualgate = (55, 0)
v5_xtor = (112, 1)
lvpwell = (204, 0)

gf180mcu_fd_sc_mcu7t5v0_ = lib.new_cell('gf180mcu_fd_sc_mcu7t5v0__nor2_1')
R(gf180mcu_fd_sc_mcu7t5v0_, boundary, [(0,0,3.36,3.92)])
R(gf180mcu_fd_sc_mcu7t5v0_, nwell, [(-0.43,1.76,3.79,4.35)])
R(gf180mcu_fd_sc_mcu7t5v0_, comp, [(0.18,0.525,2.78,1.09), (0.18,2.36,2.73,3.58)])
P(gf180mcu_fd_sc_mcu7t5v0_, poly2, [(0.62,0.305),(0.62,3.8),(1.12,3.8),(1.12,1.315),(1.22,1.315),(1.22,0.305)],
  [(1.74,0.305),(1.74,1.315),(1.79,1.315),(1.79,3.8),(2.29,3.8),(2.29,1.315),(2.34,1.315),(2.34,0.305)])
R(gf180mcu_fd_sc_mcu7t5v0_, pplus, [(-0.2,1.76,3.56,4.12)])
R(gf180mcu_fd_sc_mcu7t5v0_, nplus, [(-0.2,-0.2,3.56,1.76)])
R(gf180mcu_fd_sc_mcu7t5v0_, contact, [(0.25,0.665,0.47,0.885), (2.49,0.665,2.71,0.885), (1.37,0.735,1.59,0.955), (0.74,1.345,0.96,1.565), (1.86,1.345,2.08,1.565), (0.74,1.815,0.96,2.035), (1.86,1.815,2.08,2.035), (0.25,2.63,0.47,2.85), (2.44,2.63,2.66,2.85), (0.25,3.1,0.47,3.32), (2.44,3.1,2.66,3.32)])
R(gf180mcu_fd_sc_mcu7t5v0_, metal1, [(0.705,1.18,1.01,3.32)])
P(gf180mcu_fd_sc_mcu7t5v0_, metal1, [(1.24,0.6),(1.24,2.68),(2.385,2.68),(2.385,3.38),(2.665,3.38),(2.665,2.36),(1.595,2.36),(1.595,0.6)],
  [(1.825,0.6),(1.825,2.13),(2.855,2.13),(2.855,1.79),(2.13,1.79),(2.13,0.6)],
  [(0,-0.3),(0,0.3),(0.245,0.3),(0.245,0.945),(0.475,0.945),(0.475,0.3),(2.485,0.3),(2.485,1.09),(2.715,1.09),(2.715,0.3),(3.36,0.3),(3.36,-0.3)],
  [(0.245,2.53),(0.245,3.62),(0,3.62),(0,4.22),(3.36,4.22),(3.36,3.62),(0.475,3.62),(0.475,2.53)])
R(gf180mcu_fd_sc_mcu7t5v0_, dualgate, [(-0.28,-0.28,3.64,4.2)])
R(gf180mcu_fd_sc_mcu7t5v0_, v5_xtor, [(0,0,3.36,3.92)])
R(gf180mcu_fd_sc_mcu7t5v0_, lvpwell, [(-0.43,-0.43,3.79,1.76)])
gf180mcu_fd_sc_mcu7t5v0_.add(gdstk.Label('VDD', (1.68,3.925), layer=34, texttype=10))
gf180mcu_fd_sc_mcu7t5v0_.add(gdstk.Label('VSS', (1.68,0), layer=34, texttype=10))
gf180mcu_fd_sc_mcu7t5v0_.add(gdstk.Label('ZN', (1.96,2.52), layer=34, texttype=10))
gf180mcu_fd_sc_mcu7t5v0_.add(gdstk.Label('A1', (1.96,1.4), layer=34, texttype=10))
gf180mcu_fd_sc_mcu7t5v0_.add(gdstk.Label('A2', (0.84,2.52), layer=34, texttype=10))
gf180mcu_fd_sc_mcu7t5v0_.add(gdstk.Label('& Vendor GLOBALFOUNDRIES', (0,2), layer=63, texttype=63))
gf180mcu_fd_sc_mcu7t5v0_.add(gdstk.Label('& Product GF018hv5v_mcu_sc7', (0,1.5), layer=63, texttype=63))
gf180mcu_fd_sc_mcu7t5v0_.add(gdstk.Label('& Version 2015q2v1', (0,1), layer=63, texttype=63))
gf180mcu_fd_sc_mcu7t5v0_.add(gdstk.Label('& Metric 1.00', (0,0.5), layer=63, texttype=63))
gf180mcu_fd_sc_mcu7t5v0_.add(gdstk.Label('VNW', (0.345,3.92), layer=21, texttype=10))
gf180mcu_fd_sc_mcu7t5v0_.add(gdstk.Label('VPW', (0.34,-0.085), layer=204, texttype=10))

lib.write_gds('gf180mcu_fd_sc_mcu7t5v0__nor2_1.gds')
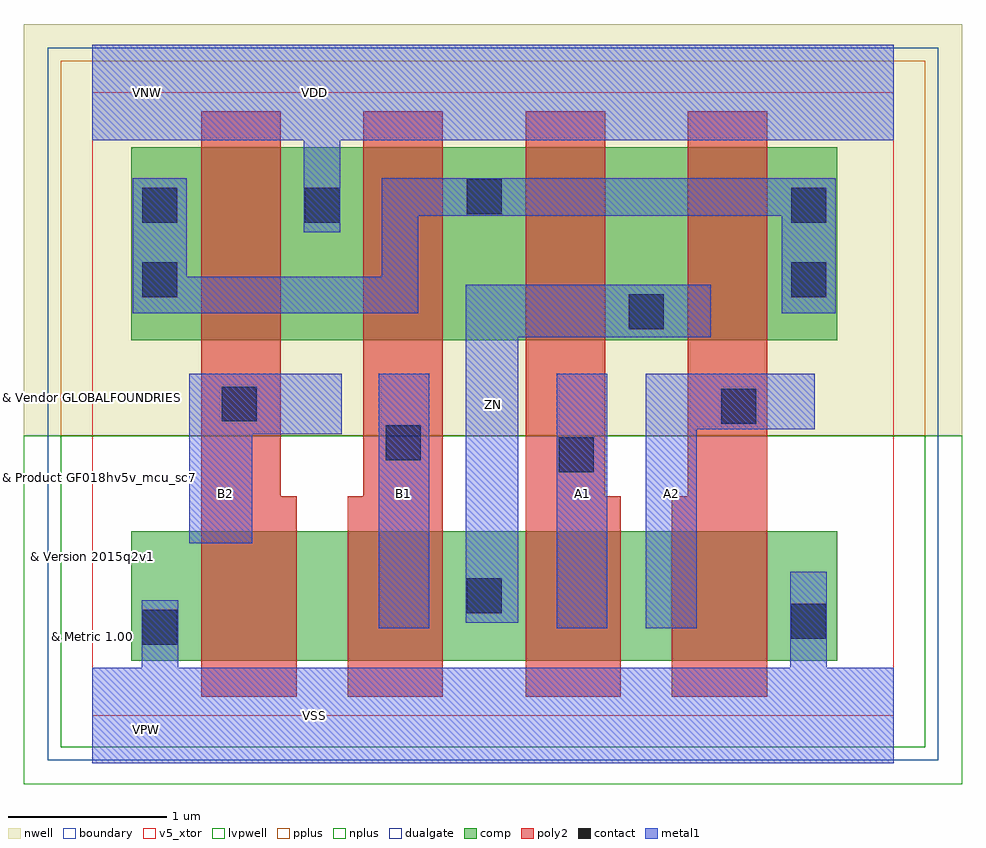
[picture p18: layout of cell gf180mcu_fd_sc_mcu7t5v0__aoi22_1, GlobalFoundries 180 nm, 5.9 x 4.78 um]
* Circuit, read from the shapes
.subckt gf180mcu_fd_sc_mcu7t5v0__aoi22_1 A1 A2 B1 B2 VDD VNW VSS ZN
XM1 n1 B2 VSS VSUBS nfet_05v0 w=0.815u l=0.6u
XM2 ZN B1 n1 VSUBS nfet_05v0 w=0.815u l=0.6u
XM3 n2 A1 ZN VSUBS nfet_05v0 w=0.815u l=0.6u
XM4 VSS A2 n2 VSUBS nfet_05v0 w=0.815u l=0.6u
XM5 VDD B2 n3 VNW pfet_05v0 w=1.215u l=0.5u
XM6 n3 B1 VDD VNW pfet_05v0 w=1.215u l=0.5u
XM7 ZN A1 n3 VNW pfet_05v0 w=1.215u l=0.5u
XM8 n3 A2 ZN VNW pfet_05v0 w=1.215u l=0.5u
.ends

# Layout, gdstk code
import gdstk
lib = gdstk.Library(unit=1e-6, precision=5e-09)
def R(c, l, rs):  # rectangles x0, y0, x1, y1
    for r in rs: c.add(gdstk.rectangle(r[:2], r[2:], *l))
def P(c, l, *ps):  # polygons
    for p in ps: c.add(gdstk.Polygon(p, *l))
boundary = (0, 0)
nwell = (21, 0)
comp = (22, 0)
poly2 = (30, 0)
pplus = (31, 0)
nplus = (32, 0)
contact = (33, 0)
metal1 = (34, 0)
dualgate = (55, 0)
v5_xtor = (112, 1)
lvpwell = (204, 0)

gf180mcu_fd_sc_mcu7t5v0_ = lib.new_cell('gf180mcu_fd_sc_mcu7t5v0__aoi22_1')
R(gf180mcu_fd_sc_mcu7t5v0_, boundary, [(0,0,5.04,3.92)])
R(gf180mcu_fd_sc_mcu7t5v0_, nwell, [(-0.43,1.76,5.47,4.35)])
R(gf180mcu_fd_sc_mcu7t5v0_, comp, [(0.245,0.345,4.685,1.16), (0.245,2.36,4.685,3.575)])
P(gf180mcu_fd_sc_mcu7t5v0_, poly2, [(0.685,0.12),(0.685,3.8),(1.185,3.8),(1.185,1.38),(1.285,1.38),(1.285,0.12)],
  [(1.605,0.12),(1.605,1.38),(1.705,1.38),(1.705,3.8),(2.205,3.8),(2.205,0.12)],
  [(2.725,0.12),(2.725,3.8),(3.225,3.8),(3.225,1.38),(3.325,1.38),(3.325,0.12)],
  [(3.645,0.12),(3.645,1.38),(3.745,1.38),(3.745,3.8),(4.245,3.8),(4.245,0.12)])
R(gf180mcu_fd_sc_mcu7t5v0_, pplus, [(-0.2,1.76,5.24,4.12)])
R(gf180mcu_fd_sc_mcu7t5v0_, nplus, [(-0.2,-0.2,5.24,1.76)])
R(gf180mcu_fd_sc_mcu7t5v0_, contact, [(0.315,0.445,0.535,0.665), (4.395,0.485,4.615,0.705), (2.355,0.645,2.575,0.865), (2.935,1.53,3.155,1.75), (1.845,1.605,2.065,1.825), (3.955,1.835,4.175,2.055), (0.815,1.85,1.035,2.07), (3.375,2.43,3.595,2.65), (0.315,2.63,0.535,2.85), (4.395,2.63,4.615,2.85), (0.315,3.1,0.535,3.32), (1.335,3.1,1.555,3.32), (4.395,3.1,4.615,3.32), (2.355,3.155,2.575,3.375)])
R(gf180mcu_fd_sc_mcu7t5v0_, metal1, [(1.8,0.55,2.12,2.15), (2.92,0.55,3.24,2.15)])
P(gf180mcu_fd_sc_mcu7t5v0_, metal1, [(0.61,1.085),(0.61,2.15),(1.57,2.15),(1.57,1.77),(1.005,1.77),(1.005,1.085)],
  [(2.35,0.585),(2.35,2.71),(3.89,2.71),(3.89,2.38),(2.68,2.38),(2.68,0.585)],
  [(3.48,0.55),(3.48,2.15),(4.545,2.15),(4.545,1.8),(3.8,1.8),(3.8,0.55)],
  [(0.255,2.53),(0.255,3.38),(0.595,3.38),(0.595,2.76),(1.82,2.76),(1.82,3.38),(4.675,3.38),(4.675,2.53),(4.335,2.53),(4.335,3.145),(2.05,3.145),(2.05,2.53)],
  [(0,-0.3),(0,0.3),(0.31,0.3),(0.31,0.725),(0.54,0.725),(0.54,0.3),(4.39,0.3),(4.39,0.905),(4.62,0.905),(4.62,0.3),(5.04,0.3),(5.04,-0.3)],
  [(1.33,3.04),(1.33,3.62),(0,3.62),(0,4.22),(5.04,4.22),(5.04,3.62),(1.56,3.62),(1.56,3.04)])
R(gf180mcu_fd_sc_mcu7t5v0_, dualgate, [(-0.28,-0.28,5.32,4.2)])
R(gf180mcu_fd_sc_mcu7t5v0_, v5_xtor, [(0,0,5.04,3.92)])
R(gf180mcu_fd_sc_mcu7t5v0_, lvpwell, [(-0.43,-0.43,5.47,1.76)])
gf180mcu_fd_sc_mcu7t5v0_.add(gdstk.Label('B1', (1.96,1.4), layer=34, texttype=10))
gf180mcu_fd_sc_mcu7t5v0_.add(gdstk.Label('B2', (0.84,1.4), layer=34, texttype=10))
gf180mcu_fd_sc_mcu7t5v0_.add(gdstk.Label('VDD', (1.4,3.92), layer=34, texttype=10))
gf180mcu_fd_sc_mcu7t5v0_.add(gdstk.Label('VSS', (1.4,0), layer=34, texttype=10))
gf180mcu_fd_sc_mcu7t5v0_.add(gdstk.Label('ZN', (2.52,1.96), layer=34, texttype=10))
gf180mcu_fd_sc_mcu7t5v0_.add(gdstk.Label('A1', (3.08,1.4), layer=34, texttype=10))
gf180mcu_fd_sc_mcu7t5v0_.add(gdstk.Label('A2', (3.64,1.4), layer=34, texttype=10))
gf180mcu_fd_sc_mcu7t5v0_.add(gdstk.Label('& Vendor GLOBALFOUNDRIES', (0,2), layer=63, texttype=63))
gf180mcu_fd_sc_mcu7t5v0_.add(gdstk.Label('& Product GF018hv5v_mcu_sc7', (0,1.5), layer=63, texttype=63))
gf180mcu_fd_sc_mcu7t5v0_.add(gdstk.Label('& Version 2015q2v1', (0,1), layer=63, texttype=63))
gf180mcu_fd_sc_mcu7t5v0_.add(gdstk.Label('& Metric 1.00', (0,0.5), layer=63, texttype=63))
gf180mcu_fd_sc_mcu7t5v0_.add(gdstk.Label('VNW', (0.345,3.92), layer=21, texttype=10))
gf180mcu_fd_sc_mcu7t5v0_.add(gdstk.Label('VPW', (0.34,-0.085), layer=204, texttype=10))

lib.write_gds('gf180mcu_fd_sc_mcu7t5v0__aoi22_1.gds')
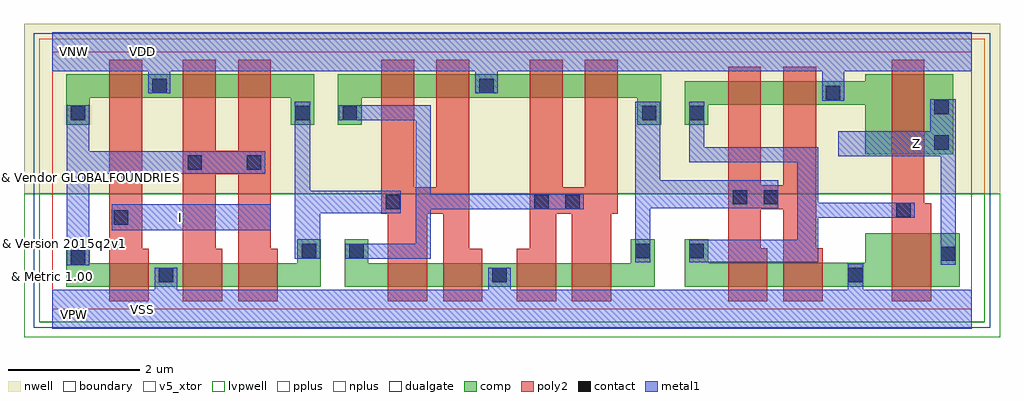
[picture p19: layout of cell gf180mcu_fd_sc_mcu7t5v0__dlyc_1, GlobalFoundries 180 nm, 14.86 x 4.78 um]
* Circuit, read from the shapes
.subckt gf180mcu_fd_sc_mcu7t5v0__dlyc_1 I VDD VNW VSS Z
XM1 VSS I n1 VSUBS nfet_05v0 w=0.36u l=0.6u
XM2 n2 n1 VSS VSUBS nfet_05v0 w=0.36u l=0.6u
XM3 n3 n1 n2 VSUBS nfet_05v0 w=0.36u l=0.6u
XM4 n4 n3 n5 VSUBS nfet_05v0 w=0.36u l=0.6u
XM5 VSS n3 n4 VSUBS nfet_05v0 w=0.36u l=0.6u
XM6 n6 n5 VSS VSUBS nfet_05v0 w=0.36u l=0.6u
XM7 n7 n5 n6 VSUBS nfet_05v0 w=0.36u l=0.6u
XM8 n8 n7 n9 VSUBS nfet_05v0 w=0.365u l=0.6u
XM9 VSS n7 n8 VSUBS nfet_05v0 w=0.365u l=0.6u
XM10 Z n9 VSS VSUBS nfet_05v0 w=0.82u l=0.6u
XM11 VDD I n1 VNW pfet_05v0 w=0.36u l=0.5u
XM12 n10 n1 VDD VNW pfet_05v0 w=0.36u l=0.5u
XM13 n3 n1 n10 VNW pfet_05v0 w=0.36u l=0.5u
XM14 n11 n3 n5 VNW pfet_05v0 w=0.36u l=0.5u
XM15 VDD n3 n11 VNW pfet_05v0 w=0.36u l=0.5u
XM16 n12 n5 VDD VNW pfet_05v0 w=0.36u l=0.5u
XM17 n7 n5 n12 VNW pfet_05v0 w=0.36u l=0.5u
XM18 n13 n7 n9 VNW pfet_05v0 w=0.36u l=0.5u
XM19 VDD n7 n13 VNW pfet_05v0 w=0.36u l=0.5u
XM20 Z n9 VDD VNW pfet_05v0 w=1.22u l=0.5u
.ends

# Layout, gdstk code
import gdstk
lib = gdstk.Library(unit=1e-6, precision=5e-09)
def R(c, l, rs):  # rectangles x0, y0, x1, y1
    for r in rs: c.add(gdstk.rectangle(r[:2], r[2:], *l))
def P(c, l, *ps):  # polygons
    for p in ps: c.add(gdstk.Polygon(p, *l))
boundary = (0, 0)
nwell = (21, 0)
comp = (22, 0)
poly2 = (30, 0)
pplus = (31, 0)
nplus = (32, 0)
contact = (33, 0)
metal1 = (34, 0)
dualgate = (55, 0)
v5_xtor = (112, 1)
lvpwell = (204, 0)

gf180mcu_fd_sc_mcu7t5v0_ = lib.new_cell('gf180mcu_fd_sc_mcu7t5v0__dlyc_1')
R(gf180mcu_fd_sc_mcu7t5v0_, boundary, [(0,0,14,3.92)])
R(gf180mcu_fd_sc_mcu7t5v0_, nwell, [(-0.43,1.76,14.43,4.35)])
P(gf180mcu_fd_sc_mcu7t5v0_, comp, [(0.21,2.81),(0.21,3.58),(3.99,3.58),(3.99,2.81),(3.63,2.81),(3.63,3.22),(0.57,3.22),(0.57,2.81)],
  [(0.21,0.34),(0.21,0.965),(0.57,0.965),(0.57,0.7),(3.73,0.7),(3.73,1.065),(4.09,1.065),(4.09,0.34)],
  [(4.45,0.34),(4.45,1.065),(4.81,1.065),(4.81,0.7),(8.81,0.7),(8.81,1.065),(9.17,1.065),(9.17,0.34)],
  [(4.35,2.81),(4.35,3.58),(9.27,3.58),(9.27,2.81),(8.91,2.81),(8.91,3.22),(4.71,3.22),(4.71,2.81)],
  [(12.38,2.36),(12.38,3.11),(9.99,3.11),(9.99,2.81),(9.63,2.81),(9.63,3.47),(12.38,3.47),(12.38,3.58),(13.72,3.58),(13.72,2.36)],
  [(9.63,0.34),(9.63,1.065),(9.99,1.065),(9.99,0.705),(12.38,0.705),(12.38,1.16),(13.82,1.16),(13.82,0.34)])
P(gf180mcu_fd_sc_mcu7t5v0_, poly2, [(0.87,0.12),(0.87,3.8),(1.37,3.8),(1.37,0.92),(1.47,0.92),(1.47,0.12)],
  [(1.99,0.12),(1.99,3.8),(2.49,3.8),(2.49,2.415),(2.83,2.415),(2.83,3.8),(3.33,3.8),(3.33,0.92),(3.43,0.92),(3.43,0.12),(2.83,0.12),(2.83,2.055),(2.49,2.055),(2.49,0.92),(2.59,0.92),(2.59,0.12)],
  [(5.11,0.12),(5.11,1.45),(5.01,1.45),(5.01,3.8),(5.51,3.8),(5.51,1.855),(5.85,1.855),(5.85,3.8),(6.35,3.8),(6.35,0.92),(6.55,0.92),(6.55,0.12),(5.95,0.12),(5.95,1.45),(5.71,1.45),(5.71,0.12)],
  [(7.07,0.12),(7.07,0.92),(7.27,0.92),(7.27,3.8),(7.77,3.8),(7.77,1.855),(8.11,1.855),(8.11,3.8),(8.61,3.8),(8.61,1.45),(8.51,1.45),(8.51,0.12),(7.91,0.12),(7.91,1.45),(7.67,1.45),(7.67,0.12)],
  [(10.29,0.12),(10.29,3.69),(10.79,3.69),(10.79,1.885),(11.13,1.885),(11.13,3.69),(11.63,3.69),(11.63,0.925),(11.73,0.925),(11.73,0.12),(11.13,0.12),(11.13,1.525),(10.79,1.525),(10.79,0.925),(10.89,0.925),(10.89,0.12)],
  [(12.78,0.12),(12.78,3.8),(13.28,3.8),(13.28,1.615),(13.38,1.615),(13.38,0.12)])
R(gf180mcu_fd_sc_mcu7t5v0_, pplus, [(-0.2,1.76,14.2,4.12)])
R(gf180mcu_fd_sc_mcu7t5v0_, nplus, [(-0.2,-0.2,14.2,1.76)])
R(gf180mcu_fd_sc_mcu7t5v0_, contact, [(1.62,0.41,1.84,0.63), (6.7,0.41,6.92,0.63), (12.12,0.41,12.34,0.63), (0.28,0.675,0.5,0.895), (13.53,0.735,13.75,0.955), (3.8,0.775,4.02,0.995), (4.52,0.775,4.74,0.995), (8.88,0.775,9.1,0.995), (9.7,0.775,9.92,0.995), (0.94,1.29,1.16,1.51), (12.85,1.4,13.07,1.62), (5.08,1.525,5.3,1.745), (7.34,1.525,7.56,1.745), (7.81,1.525,8.03,1.745), (10.36,1.595,10.58,1.815), (10.83,1.595,11.05,1.815), (2.06,2.125,2.28,2.345), (2.96,2.125,3.18,2.345), (13.43,2.43,13.65,2.65), (0.28,2.88,0.5,3.1), (3.7,2.88,3.92,3.1), (4.42,2.88,4.64,3.1), (8.98,2.88,9.2,3.1), (9.7,2.88,9.92,3.1), (13.43,2.97,13.65,3.19), (11.78,3.18,12,3.4), (1.52,3.29,1.74,3.51), (6.5,3.29,6.72,3.51)])
R(gf180mcu_fd_sc_mcu7t5v0_, metal1, [(0.905,1.2,3.33,1.6)])
P(gf180mcu_fd_sc_mcu7t5v0_, metal1, [(0.22,0.67),(0.22,3.105),(0.56,3.105),(0.56,2.405),(3.24,2.405),(3.24,2.065),(0.56,2.065),(0.56,0.67)],
  [(3.695,0.77),(3.695,3.16),(3.925,3.16),(3.925,1.805),(5.305,1.805),(5.305,1.465),(4.08,1.465),(4.08,0.77)],
  [(4.46,0.77),(4.46,1),(5.535,1),(5.535,2.875),(4.36,2.875),(4.36,3.105),(5.765,3.105),(5.765,1.75),(8.09,1.75),(8.09,1.52),(5.765,1.52),(5.765,0.77)],
  [(8.875,0.715),(8.875,3.16),(9.26,3.16),(9.26,1.965),(11.055,1.965),(11.055,1.535),(9.105,1.535),(9.105,0.715)],
  [(9.695,0.715),(9.695,1.055),(11.345,1.055),(11.345,2.235),(9.695,2.235),(9.695,3.16),(9.925,3.16),(9.925,2.465),(11.665,2.465),(11.665,1.625),(13.13,1.625),(13.13,1.395),(11.665,1.395),(11.665,0.715)],
  [(13.525,0.675),(13.525,2.33),(11.965,2.33),(11.965,2.71),(13.37,2.71),(13.37,3.195),(13.755,3.195),(13.755,0.675)],
  [(0,-0.3),(0,0.3),(1.56,0.3),(1.56,0.635),(1.9,0.635),(1.9,0.3),(6.64,0.3),(6.64,0.635),(6.98,0.635),(6.98,0.3),(12.115,0.3),(12.115,0.69),(12.345,0.69),(12.345,0.3),(14,0.3),(14,-0.3)],
  [(11.72,3.175),(11.72,3.62),(6.78,3.62),(6.78,3.285),(6.44,3.285),(6.44,3.62),(1.8,3.62),(1.8,3.285),(1.46,3.285),(1.46,3.62),(0,3.62),(0,4.22),(14,4.22),(14,3.62),(12.06,3.62),(12.06,3.175)])
R(gf180mcu_fd_sc_mcu7t5v0_, dualgate, [(-0.28,-0.28,14.28,4.2)])
R(gf180mcu_fd_sc_mcu7t5v0_, v5_xtor, [(0,0,14,3.92)])
R(gf180mcu_fd_sc_mcu7t5v0_, lvpwell, [(-0.43,-0.43,14.43,1.76)])
gf180mcu_fd_sc_mcu7t5v0_.add(gdstk.Label('Z', (13.16,2.52), layer=34, texttype=10))
gf180mcu_fd_sc_mcu7t5v0_.add(gdstk.Label('VSS', (1.375,0), layer=34, texttype=10))
gf180mcu_fd_sc_mcu7t5v0_.add(gdstk.Label('I', (1.96,1.4), layer=34, texttype=10))
gf180mcu_fd_sc_mcu7t5v0_.add(gdstk.Label('VDD', (1.375,3.92), layer=34, texttype=10))
gf180mcu_fd_sc_mcu7t5v0_.add(gdstk.Label('& Vendor GLOBALFOUNDRIES', (0,2), layer=63, texttype=63))
gf180mcu_fd_sc_mcu7t5v0_.add(gdstk.Label('& Product GF018hv5v_mcu_sc7', (0,1.5), layer=63, texttype=63))
gf180mcu_fd_sc_mcu7t5v0_.add(gdstk.Label('& Version 2015q2v1', (0,1), layer=63, texttype=63))
gf180mcu_fd_sc_mcu7t5v0_.add(gdstk.Label('& Metric 1.00', (0,0.5), layer=63, texttype=63))
gf180mcu_fd_sc_mcu7t5v0_.add(gdstk.Label('VNW', (0.345,3.92), layer=21, texttype=10))
gf180mcu_fd_sc_mcu7t5v0_.add(gdstk.Label('VPW', (0.34,-0.085), layer=204, texttype=10))

lib.write_gds('gf180mcu_fd_sc_mcu7t5v0__dlyc_1.gds')
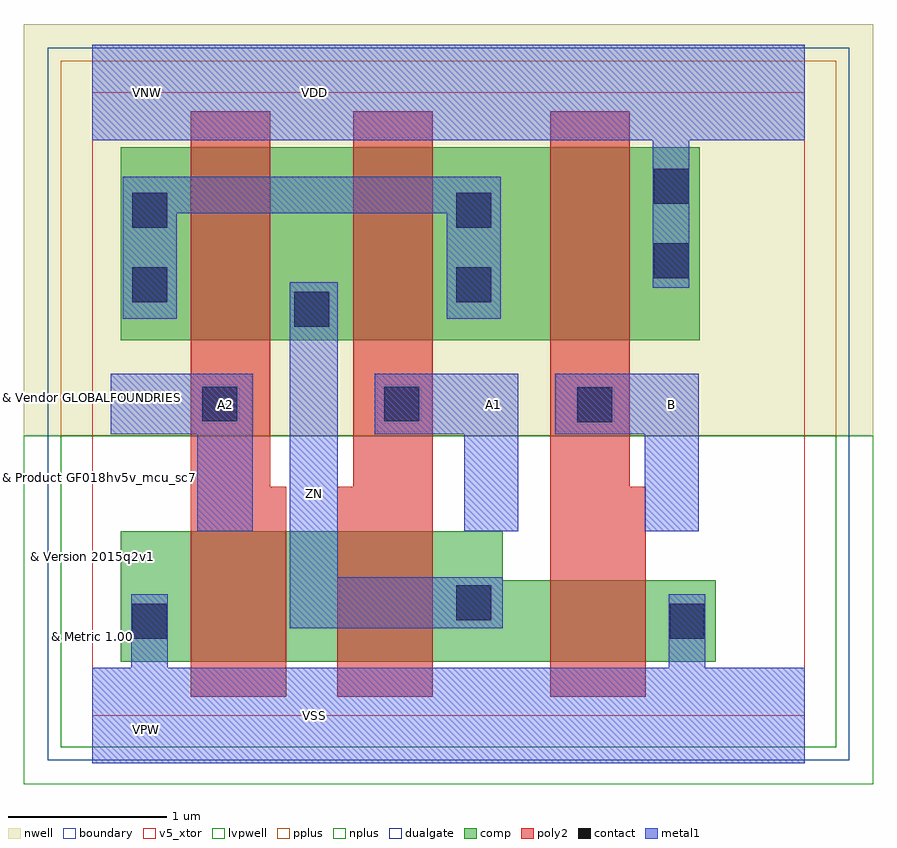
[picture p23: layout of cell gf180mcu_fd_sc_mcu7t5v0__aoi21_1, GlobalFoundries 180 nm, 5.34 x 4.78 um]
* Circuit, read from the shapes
.subckt gf180mcu_fd_sc_mcu7t5v0__aoi21_1 A1 A2 B VDD VNW VSS ZN
XM1 n1 A2 VSS VSUBS nfet_05v0 w=0.82u l=0.6u
XM2 ZN A1 n1 VSUBS nfet_05v0 w=0.82u l=0.6u
XM3 VSS B ZN VSUBS nfet_05v0 w=0.51u l=0.6u
XM4 ZN A2 n2 VNW pfet_05v0 w=1.215u l=0.5u
XM5 n2 A1 ZN VNW pfet_05v0 w=1.215u l=0.5u
XM6 VDD B n2 VNW pfet_05v0 w=1.215u l=0.5u
.ends

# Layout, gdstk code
import gdstk
lib = gdstk.Library(unit=1e-6, precision=5e-09)
def R(c, l, rs):  # rectangles x0, y0, x1, y1
    for r in rs: c.add(gdstk.rectangle(r[:2], r[2:], *l))
def P(c, l, *ps):  # polygons
    for p in ps: c.add(gdstk.Polygon(p, *l))
boundary = (0, 0)
nwell = (21, 0)
comp = (22, 0)
poly2 = (30, 0)
pplus = (31, 0)
nplus = (32, 0)
contact = (33, 0)
metal1 = (34, 0)
dualgate = (55, 0)
v5_xtor = (112, 1)
lvpwell = (204, 0)

gf180mcu_fd_sc_mcu7t5v0_ = lib.new_cell('gf180mcu_fd_sc_mcu7t5v0__aoi21_1')
R(gf180mcu_fd_sc_mcu7t5v0_, boundary, [(0,0,4.48,3.92)])
R(gf180mcu_fd_sc_mcu7t5v0_, nwell, [(-0.43,1.76,4.91,4.35)])
R(gf180mcu_fd_sc_mcu7t5v0_, comp, [(0.18,2.36,3.82,3.575)])
P(gf180mcu_fd_sc_mcu7t5v0_, comp, [(0.18,0.34),(0.18,1.16),(2.58,1.16),(2.58,0.85),(3.92,0.85),(3.92,0.34)])
P(gf180mcu_fd_sc_mcu7t5v0_, poly2, [(0.62,0.12),(0.62,3.8),(1.12,3.8),(1.12,1.44),(1.22,1.44),(1.22,0.12)],
  [(1.54,0.12),(1.54,1.44),(1.64,1.44),(1.64,3.8),(2.14,3.8),(2.14,0.12)],
  [(2.88,0.12),(2.88,3.8),(3.38,3.8),(3.38,1.44),(3.48,1.44),(3.48,0.12)])
R(gf180mcu_fd_sc_mcu7t5v0_, pplus, [(-0.2,1.76,4.68,4.12)])
R(gf180mcu_fd_sc_mcu7t5v0_, nplus, [(-0.2,-0.2,4.68,1.76)])
R(gf180mcu_fd_sc_mcu7t5v0_, contact, [(0.25,0.485,0.47,0.705), (3.63,0.485,3.85,0.705), (2.29,0.6,2.51,0.82), (3.05,1.845,3.27,2.065), (0.69,1.85,0.91,2.07), (1.835,1.85,2.055,2.07), (1.27,2.445,1.49,2.665), (0.25,2.6,0.47,2.82), (2.29,2.6,2.51,2.82), (3.53,2.75,3.75,2.97), (0.25,3.07,0.47,3.29), (2.29,3.07,2.51,3.29), (3.53,3.22,3.75,3.44)])
P(gf180mcu_fd_sc_mcu7t5v0_, metal1, [(0.66,1.16),(0.66,1.77),(0.115,1.77),(0.115,2.15),(1.01,2.15),(1.01,1.16)],
  [(0.19,2.495),(0.19,3.39),(2.57,3.39),(2.57,2.495),(2.23,2.495),(2.23,3.16),(0.53,3.16),(0.53,2.495)],
  [(1.24,0.55),(1.24,2.725),(1.545,2.725),(1.545,0.87),(2.58,0.87),(2.58,0.55)],
  [(2.34,1.16),(2.34,1.77),(1.775,1.77),(1.775,2.15),(2.68,2.15),(2.68,1.16)],
  [(3.475,1.16),(3.475,1.77),(2.91,1.77),(2.91,2.15),(3.815,2.15),(3.815,1.16)],
  [(0,-0.3),(0,0.3),(0.245,0.3),(0.245,0.765),(0.475,0.765),(0.475,0.3),(3.625,0.3),(3.625,0.765),(3.855,0.765),(3.855,0.3),(4.48,0.3),(4.48,-0.3)],
  [(3.525,2.69),(3.525,3.62),(0,3.62),(0,4.22),(4.48,4.22),(4.48,3.62),(3.755,3.62),(3.755,2.69)])
R(gf180mcu_fd_sc_mcu7t5v0_, dualgate, [(-0.28,-0.28,4.76,4.2)])
R(gf180mcu_fd_sc_mcu7t5v0_, v5_xtor, [(0,0,4.48,3.92)])
R(gf180mcu_fd_sc_mcu7t5v0_, lvpwell, [(-0.43,-0.43,4.91,1.76)])
gf180mcu_fd_sc_mcu7t5v0_.add(gdstk.Label('B', (3.64,1.96), layer=34, texttype=10))
gf180mcu_fd_sc_mcu7t5v0_.add(gdstk.Label('VDD', (1.4,3.92), layer=34, texttype=10))
gf180mcu_fd_sc_mcu7t5v0_.add(gdstk.Label('VSS', (1.4,0), layer=34, texttype=10))
gf180mcu_fd_sc_mcu7t5v0_.add(gdstk.Label('ZN', (1.4,1.4), layer=34, texttype=10))
gf180mcu_fd_sc_mcu7t5v0_.add(gdstk.Label('A1', (2.52,1.96), layer=34, texttype=10))
gf180mcu_fd_sc_mcu7t5v0_.add(gdstk.Label('A2', (0.84,1.96), layer=34, texttype=10))
gf180mcu_fd_sc_mcu7t5v0_.add(gdstk.Label('& Vendor GLOBALFOUNDRIES', (0,2), layer=63, texttype=63))
gf180mcu_fd_sc_mcu7t5v0_.add(gdstk.Label('& Product GF018hv5v_mcu_sc7', (0,1.5), layer=63, texttype=63))
gf180mcu_fd_sc_mcu7t5v0_.add(gdstk.Label('& Version 2015q2v1', (0,1), layer=63, texttype=63))
gf180mcu_fd_sc_mcu7t5v0_.add(gdstk.Label('& Metric 1.00', (0,0.5), layer=63, texttype=63))
gf180mcu_fd_sc_mcu7t5v0_.add(gdstk.Label('VNW', (0.345,3.92), layer=21, texttype=10))
gf180mcu_fd_sc_mcu7t5v0_.add(gdstk.Label('VPW', (0.34,-0.085), layer=204, texttype=10))

lib.write_gds('gf180mcu_fd_sc_mcu7t5v0__aoi21_1.gds')
